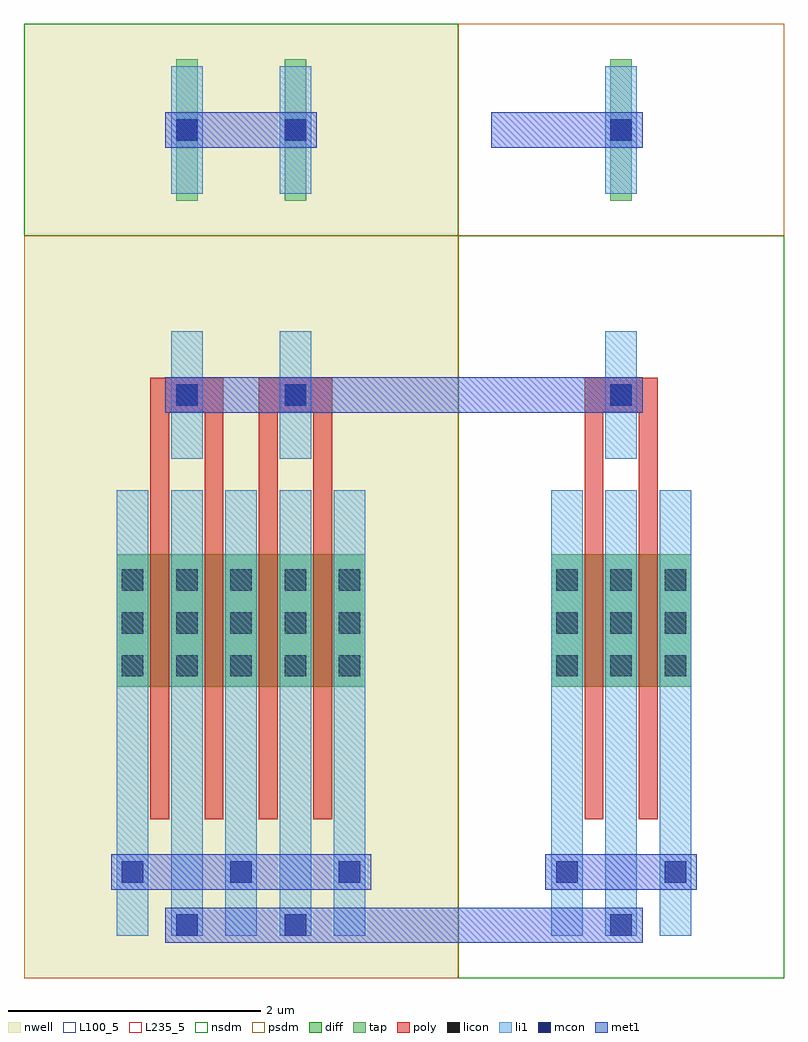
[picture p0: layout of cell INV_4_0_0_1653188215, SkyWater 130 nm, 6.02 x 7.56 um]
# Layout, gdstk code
import gdstk
lib = gdstk.Library(unit=1e-6, precision=1e-09)
def R(c, l, rs):  # rectangles x0, y0, x1, y1
    for r in rs: c.add(gdstk.rectangle(r[:2], r[2:], *l))
def A(c, l, x, y, w, h, nx, ny, dx, dy):  # array of equal rectangles
    R(c, l, [(x+i*dx, y+j*dy, x+i*dx+w, y+j*dy+h) for i in range(nx) for j in range(ny)])
def P(c, l, *ps):  # polygons
    for p in ps: c.add(gdstk.Polygon(p, *l))
nwell = (64, 20)
diff = (65, 20)
tap = (65, 44)
poly = (66, 20)
licon = (66, 44)
li1 = (67, 20)
mcon = (67, 44)
met1 = (68, 20)
nsdm = (93, 44)
psdm = (94, 20)
L100_5 = (100, 5)
L235_5 = (235, 5)

nmos_4t_61669136_x1_y1_1 = lib.new_cell('NMOS_4T_61669136_X1_Y1_1653188207_1653188215')
R(nmos_4t_61669136_x1_y1_1, diff, [(0.735,2.31,1.845,3.36)])
R(nmos_4t_61669136_x1_y1_1, tap, [(1.205,6.16,1.375,7.28)])
R(nmos_4t_61669136_x1_y1_1, poly, [(1,1.26,1.15,4.62), (1.43,1.26,1.58,4.62), (1,4.485,1.58,4.755)])
A(nmos_4t_61669136_x1_y1_1, licon, 0.775, 2.39, 0.17, 0.17, 3, 3, 0.43, 0.34)
R(nmos_4t_61669136_x1_y1_1, licon, [(1.205,4.535,1.375,4.705), (1.205,6.635,1.375,6.805)])
A(nmos_4t_61669136_x1_y1_1, li1, 0.735, 0.335, 0.25, 3.53, 3, 1, 0.43, 0)
R(nmos_4t_61669136_x1_y1_1, li1, [(1.165,4.115,1.415,5.125), (1.165,6.215,1.415,7.225)])
R(nmos_4t_61669136_x1_y1_1, mcon, [(1.205,0.335,1.375,0.505), (0.775,0.755,0.945,0.925), (1.635,0.755,1.805,0.925), (1.205,4.535,1.375,4.705), (1.205,6.635,1.375,6.805)])
R(nmos_4t_61669136_x1_y1_1, met1, [(0.26,0.28,1.46,0.56), (0.69,0.7,1.89,0.98), (0.26,4.48,1.46,4.76), (0.26,6.58,1.46,6.86)])
R(nmos_4t_61669136_x1_y1_1, nsdm, [(0,0,2.58,5.88)])
R(nmos_4t_61669136_x1_y1_1, psdm, [(0,5.88,2.58,7.56)])
R(nmos_4t_61669136_x1_y1_1, L100_5, [(0,0,2.58,7.56)])

pmos_4t_50440855_x2_y1_1 = lib.new_cell('PMOS_4T_50440855_X2_Y1_1653188208_1653188215')
R(pmos_4t_50440855_x2_y1_1, nwell, [(0,0,3.44,7.56)])
R(pmos_4t_50440855_x2_y1_1, diff, [(0.735,2.31,2.705,3.36)])
R(pmos_4t_50440855_x2_y1_1, tap, [(1.205,6.16,1.375,7.28), (2.065,6.16,2.235,7.28)])
A(pmos_4t_50440855_x2_y1_1, poly, 1, 1.26, 0.15, 3.36, 4, 1, 0.43, 0)
R(pmos_4t_50440855_x2_y1_1, poly, [(1,4.485,1.58,4.755), (1.86,4.485,2.44,4.755)])
A(pmos_4t_50440855_x2_y1_1, licon, 0.775, 2.39, 0.17, 0.17, 3, 3, 0.43, 0.34)
A(pmos_4t_50440855_x2_y1_1, licon, 1.635, 2.39, 0.17, 0.17, 3, 3, 0.43, 0.34)
R(pmos_4t_50440855_x2_y1_1, licon, [(1.205,4.535,1.375,4.705), (2.065,4.535,2.235,4.705), (1.205,6.635,1.375,6.805), (2.065,6.635,2.235,6.805)])
A(pmos_4t_50440855_x2_y1_1, li1, 0.735, 0.335, 0.25, 3.53, 5, 1, 0.43, 0)
R(pmos_4t_50440855_x2_y1_1, li1, [(1.165,4.115,1.415,5.125), (2.025,4.115,2.275,5.125), (1.165,6.215,1.415,7.225), (2.025,6.215,2.275,7.225)])
A(pmos_4t_50440855_x2_y1_1, mcon, 0.775, 0.755, 0.17, 0.17, 3, 1, 0.86, 0)
R(pmos_4t_50440855_x2_y1_1, mcon, [(1.205,0.335,1.375,0.505), (2.065,0.335,2.235,0.505), (1.205,4.535,1.375,4.705), (2.065,4.535,2.235,4.705), (1.205,6.635,1.375,6.805), (2.065,6.635,2.235,6.805)])
R(pmos_4t_50440855_x2_y1_1, met1, [(1.12,0.28,2.32,0.56), (0.69,0.7,2.75,0.98), (1.12,4.48,2.32,4.76), (1.12,6.58,2.32,6.86)])
R(pmos_4t_50440855_x2_y1_1, nsdm, [(0,5.88,3.44,7.56)])
R(pmos_4t_50440855_x2_y1_1, psdm, [(0,0,3.44,5.88)])
R(pmos_4t_50440855_x2_y1_1, L100_5, [(0,0,3.44,7.56)])

inv_4_0_0_1653188215 = lib.new_cell('INV_4_0_0_1653188215')
R(inv_4_0_0_1653188215, met1, [(2.15,0.28,3.87,0.56), (2.15,4.48,3.87,4.76)])
P(inv_4_0_0_1653188215, met1, [(0,0),(0,0),(0,0),(0,0)],
  [(0,0),(0,0),(0,0),(0,0)],
  [(0,0),(0,0),(0,0),(0,0)],
  [(0,0),(0,0),(0,0),(0,0)],
  [(0,0),(0,0),(0,0),(0,0)],
  [(0,0),(0,0),(0,0),(0,0)],
  [(0,0),(0,0),(0,0),(0,0)],
  [(0,0),(0,0),(0,0),(0,0)])
R(inv_4_0_0_1653188215, L235_5, [(0,0,6.02,7.56)])
inv_4_0_0_1653188215.add(gdstk.Reference(nmos_4t_61669136_x1_y1_1, (3.44,0)))
inv_4_0_0_1653188215.add(gdstk.Reference(pmos_4t_50440855_x2_y1_1, (0,0)))

lib.write_gds('INV_4_0_0_1653188215.gds')
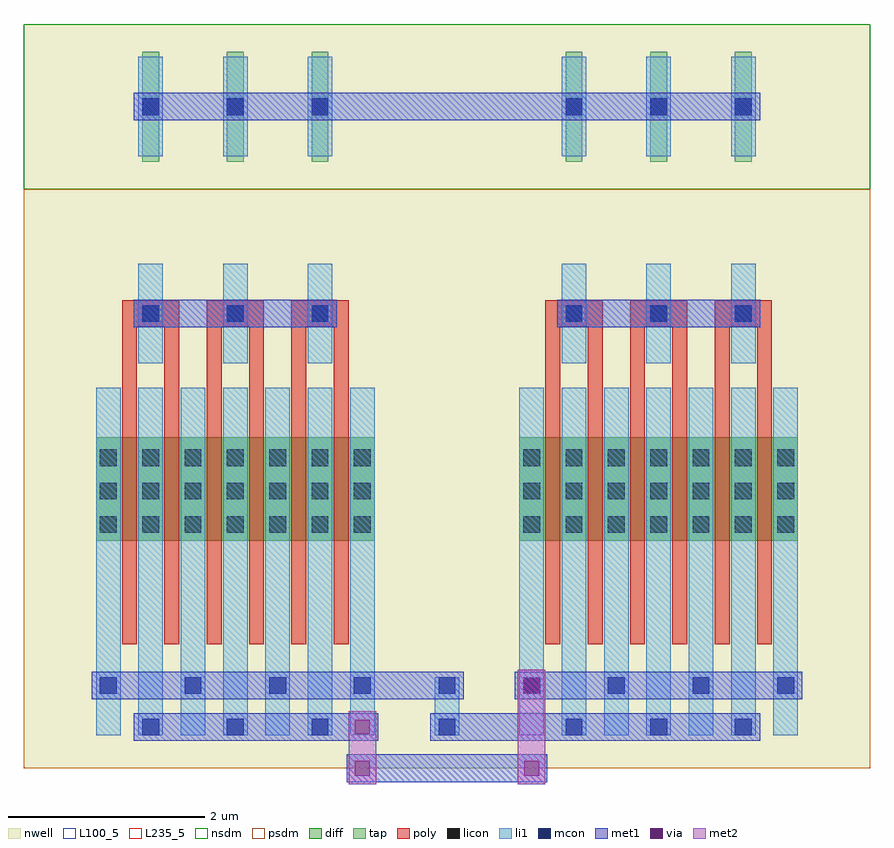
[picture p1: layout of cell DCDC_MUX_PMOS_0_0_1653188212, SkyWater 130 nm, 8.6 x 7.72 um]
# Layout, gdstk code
from math import pi, radians
import gdstk
lib = gdstk.Library(unit=1e-6, precision=1e-09)
def R(c, l, rs):  # rectangles x0, y0, x1, y1
    for r in rs: c.add(gdstk.rectangle(r[:2], r[2:], *l))
def A(c, l, x, y, w, h, nx, ny, dx, dy):  # array of equal rectangles
    R(c, l, [(x+i*dx, y+j*dy, x+i*dx+w, y+j*dy+h) for i in range(nx) for j in range(ny)])
def P(c, l, *ps):  # polygons
    for p in ps: c.add(gdstk.Polygon(p, *l))
nwell = (64, 20)
diff = (65, 20)
tap = (65, 44)
poly = (66, 20)
licon = (66, 44)
li1 = (67, 20)
mcon = (67, 44)
met1 = (68, 20)
via = (68, 44)
met2 = (69, 20)
nsdm = (93, 44)
psdm = (94, 20)
L100_5 = (100, 5)
L235_5 = (235, 5)

pmos_4t_65510288_x3_y1_1 = lib.new_cell('PMOS_4T_65510288_X3_Y1_1653188207_1653188212')
R(pmos_4t_65510288_x3_y1_1, nwell, [(0,0,4.3,7.56)])
R(pmos_4t_65510288_x3_y1_1, diff, [(0.735,2.31,3.565,3.36)])
A(pmos_4t_65510288_x3_y1_1, tap, 1.205, 6.16, 0.17, 1.12, 3, 1, 0.86, 0)
A(pmos_4t_65510288_x3_y1_1, poly, 1, 1.26, 0.15, 3.36, 6, 1, 0.43, 0)
A(pmos_4t_65510288_x3_y1_1, poly, 1, 4.485, 0.58, 0.27, 3, 1, 0.86, 0)
A(pmos_4t_65510288_x3_y1_1, licon, 0.775, 2.39, 0.17, 0.17, 3, 3, 0.43, 0.34)
A(pmos_4t_65510288_x3_y1_1, licon, 1.635, 2.39, 0.17, 0.17, 3, 3, 0.43, 0.34)
A(pmos_4t_65510288_x3_y1_1, licon, 2.495, 2.39, 0.17, 0.17, 3, 3, 0.43, 0.34)
A(pmos_4t_65510288_x3_y1_1, licon, 1.205, 4.535, 0.17, 0.17, 3, 2, 0.86, 2.1)
A(pmos_4t_65510288_x3_y1_1, li1, 0.735, 0.335, 0.25, 3.53, 7, 1, 0.43, 0)
A(pmos_4t_65510288_x3_y1_1, li1, 1.165, 4.115, 0.25, 1.01, 3, 2, 0.86, 2.1)
A(pmos_4t_65510288_x3_y1_1, mcon, 1.205, 0.335, 0.17, 0.17, 3, 2, 0.86, 4.2)
A(pmos_4t_65510288_x3_y1_1, mcon, 0.775, 0.755, 0.17, 0.17, 4, 1, 0.86, 0)
A(pmos_4t_65510288_x3_y1_1, mcon, 1.205, 6.635, 0.17, 0.17, 3, 1, 0.86, 0)
R(pmos_4t_65510288_x3_y1_1, met1, [(1.12,0.28,3.18,0.56), (0.69,0.7,3.61,0.98), (1.12,4.48,3.18,4.76), (1.12,6.58,3.18,6.86)])
R(pmos_4t_65510288_x3_y1_1, nsdm, [(0,5.88,4.3,7.56)])
R(pmos_4t_65510288_x3_y1_1, psdm, [(0,0,4.3,5.88)])
R(pmos_4t_65510288_x3_y1_1, L100_5, [(0,0,4.3,7.56)])

dcdc_mux_pmos_0_0_165318 = lib.new_cell('DCDC_MUX_PMOS_0_0_1653188212')
R(dcdc_mux_pmos_0_0_165318, li1, [(4.175,0.335,4.425,0.505), (4.175,0.335,4.425,0.505), (4.175,0.42,4.425,0.84), (4.175,0.755,4.425,0.925), (4.175,0.755,4.425,0.925)])
R(dcdc_mux_pmos_0_0_165318, mcon, [(4.215,0.335,4.385,0.505), (4.215,0.335,4.385,0.505), (4.215,0.755,4.385,0.925), (4.215,0.755,4.385,0.925)])
R(dcdc_mux_pmos_0_0_165318, met1, [(3.28,-0.14,3.6,0.14), (3.28,-0.14,3.6,0.14), (3.44,-0.14,5.16,0.14), (5,-0.14,5.32,0.14), (5,-0.14,5.32,0.14), (3.01,0.28,3.44,0.56), (3.28,0.28,3.6,0.56), (3.28,0.28,3.6,0.56), (4.13,0.28,4.47,0.56), (4.13,0.28,4.47,0.56), (4.3,0.28,5.59,0.56), (3.44,0.7,4.3,0.98), (4.13,0.7,4.47,0.98), (4.13,0.7,4.47,0.98), (5,0.7,5.32,0.98), (5,0.7,5.32,0.98), (3.01,6.58,5.59,6.86)])
P(dcdc_mux_pmos_0_0_165318, met1, [(0,0),(0,0),(0,0),(0,0)],
  [(0,0),(0,0),(0,0),(0,0)],
  [(0,0),(0,0),(0,0),(0,0)],
  [(0,0),(0,0),(0,0),(0,0)],
  [(0,0),(0,0),(0,0),(0,0)],
  [(0,0),(0,0),(0,0),(0,0)],
  [(0,0),(0,0),(0,0),(0,0)],
  [(0,0),(0,0),(0,0),(0,0)])
R(dcdc_mux_pmos_0_0_165318, via, [(3.365,-0.075,3.515,0.075), (3.365,-0.075,3.515,0.075), (5.085,-0.075,5.235,0.075), (5.085,-0.075,5.235,0.075), (3.365,0.345,3.515,0.495), (3.365,0.345,3.515,0.495), (5.085,0.765,5.235,0.915), (5.085,0.765,5.235,0.915)])
R(dcdc_mux_pmos_0_0_165318, met2, [(3.3,-0.16,3.58,0.16), (3.3,-0.16,3.58,0.16), (5.02,-0.16,5.3,0.16), (5.02,-0.16,5.3,0.16), (3.3,0,3.58,0.42), (5.02,0,5.3,0.84), (3.3,0.26,3.58,0.58), (3.3,0.26,3.58,0.58), (5.02,0.68,5.3,1), (5.02,0.68,5.3,1)])
R(dcdc_mux_pmos_0_0_165318, L235_5, [(0,0,8.6,7.56)])
dcdc_mux_pmos_0_0_165318.add(gdstk.Reference(pmos_4t_65510288_x3_y1_1, (8.6,0), rotation=pi, x_reflection=True))
dcdc_mux_pmos_0_0_165318.add(gdstk.Reference(pmos_4t_65510288_x3_y1_1, (0,0)))

lib.write_gds('DCDC_MUX_PMOS_0_0_1653188212.gds')
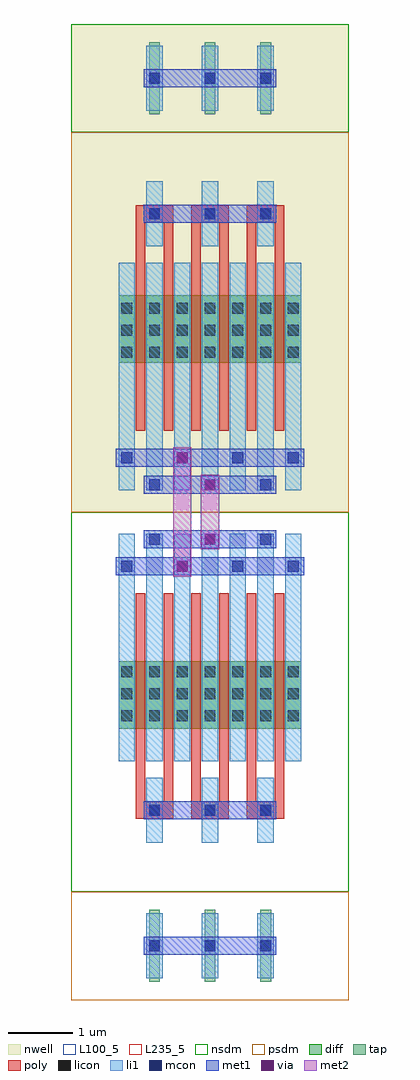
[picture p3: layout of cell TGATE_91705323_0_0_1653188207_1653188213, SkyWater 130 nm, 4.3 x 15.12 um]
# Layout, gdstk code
import gdstk
lib = gdstk.Library(unit=1e-6, precision=1e-09)
def R(c, l, rs):  # rectangles x0, y0, x1, y1
    for r in rs: c.add(gdstk.rectangle(r[:2], r[2:], *l))
def A(c, l, x, y, w, h, nx, ny, dx, dy):  # array of equal rectangles
    R(c, l, [(x+i*dx, y+j*dy, x+i*dx+w, y+j*dy+h) for i in range(nx) for j in range(ny)])
def P(c, l, *ps):  # polygons
    for p in ps: c.add(gdstk.Polygon(p, *l))
nwell = (64, 20)
diff = (65, 20)
tap = (65, 44)
poly = (66, 20)
licon = (66, 44)
li1 = (67, 20)
mcon = (67, 44)
met1 = (68, 20)
via = (68, 44)
met2 = (69, 20)
nsdm = (93, 44)
psdm = (94, 20)
L100_5 = (100, 5)
L235_5 = (235, 5)

nmos_4t_65109672_x3_y1_1 = lib.new_cell('NMOS_4T_65109672_X3_Y1_1653188207_1653188207_1653188213')
R(nmos_4t_65109672_x3_y1_1, diff, [(0.735,2.31,3.565,3.36)])
A(nmos_4t_65109672_x3_y1_1, tap, 1.205, 6.16, 0.17, 1.12, 3, 1, 0.86, 0)
A(nmos_4t_65109672_x3_y1_1, poly, 1, 1.26, 0.15, 3.36, 6, 1, 0.43, 0)
A(nmos_4t_65109672_x3_y1_1, poly, 1, 4.485, 0.58, 0.27, 3, 1, 0.86, 0)
A(nmos_4t_65109672_x3_y1_1, licon, 0.775, 2.39, 0.17, 0.17, 3, 3, 0.43, 0.34)
A(nmos_4t_65109672_x3_y1_1, licon, 1.635, 2.39, 0.17, 0.17, 3, 3, 0.43, 0.34)
A(nmos_4t_65109672_x3_y1_1, licon, 2.495, 2.39, 0.17, 0.17, 3, 3, 0.43, 0.34)
A(nmos_4t_65109672_x3_y1_1, licon, 1.205, 4.535, 0.17, 0.17, 3, 2, 0.86, 2.1)
A(nmos_4t_65109672_x3_y1_1, li1, 0.735, 0.335, 0.25, 3.53, 7, 1, 0.43, 0)
A(nmos_4t_65109672_x3_y1_1, li1, 1.165, 4.115, 0.25, 1.01, 3, 2, 0.86, 2.1)
A(nmos_4t_65109672_x3_y1_1, mcon, 1.205, 0.335, 0.17, 0.17, 3, 2, 0.86, 4.2)
A(nmos_4t_65109672_x3_y1_1, mcon, 0.775, 0.755, 0.17, 0.17, 4, 1, 0.86, 0)
A(nmos_4t_65109672_x3_y1_1, mcon, 1.205, 6.635, 0.17, 0.17, 3, 1, 0.86, 0)
R(nmos_4t_65109672_x3_y1_1, met1, [(1.12,0.28,3.18,0.56), (0.69,0.7,3.61,0.98), (1.12,4.48,3.18,4.76), (1.12,6.58,3.18,6.86)])
R(nmos_4t_65109672_x3_y1_1, nsdm, [(0,0,4.3,5.88)])
R(nmos_4t_65109672_x3_y1_1, psdm, [(0,5.88,4.3,7.56)])
R(nmos_4t_65109672_x3_y1_1, L100_5, [(0,0,4.3,7.56)])

pmos_4t_65510288_x3_y1_1 = lib.new_cell('PMOS_4T_65510288_X3_Y1_1653188208_1653188207_1653188213')
R(pmos_4t_65510288_x3_y1_1, nwell, [(0,0,4.3,7.56)])
R(pmos_4t_65510288_x3_y1_1, diff, [(0.735,2.31,3.565,3.36)])
A(pmos_4t_65510288_x3_y1_1, tap, 1.205, 6.16, 0.17, 1.12, 3, 1, 0.86, 0)
A(pmos_4t_65510288_x3_y1_1, poly, 1, 1.26, 0.15, 3.36, 6, 1, 0.43, 0)
A(pmos_4t_65510288_x3_y1_1, poly, 1, 4.485, 0.58, 0.27, 3, 1, 0.86, 0)
A(pmos_4t_65510288_x3_y1_1, licon, 0.775, 2.39, 0.17, 0.17, 3, 3, 0.43, 0.34)
A(pmos_4t_65510288_x3_y1_1, licon, 1.635, 2.39, 0.17, 0.17, 3, 3, 0.43, 0.34)
A(pmos_4t_65510288_x3_y1_1, licon, 2.495, 2.39, 0.17, 0.17, 3, 3, 0.43, 0.34)
A(pmos_4t_65510288_x3_y1_1, licon, 1.205, 4.535, 0.17, 0.17, 3, 2, 0.86, 2.1)
A(pmos_4t_65510288_x3_y1_1, li1, 0.735, 0.335, 0.25, 3.53, 7, 1, 0.43, 0)
A(pmos_4t_65510288_x3_y1_1, li1, 1.165, 4.115, 0.25, 1.01, 3, 2, 0.86, 2.1)
A(pmos_4t_65510288_x3_y1_1, mcon, 1.205, 0.335, 0.17, 0.17, 3, 2, 0.86, 4.2)
A(pmos_4t_65510288_x3_y1_1, mcon, 0.775, 0.755, 0.17, 0.17, 4, 1, 0.86, 0)
A(pmos_4t_65510288_x3_y1_1, mcon, 1.205, 6.635, 0.17, 0.17, 3, 1, 0.86, 0)
R(pmos_4t_65510288_x3_y1_1, met1, [(1.12,0.28,3.18,0.56), (0.69,0.7,3.61,0.98), (1.12,4.48,3.18,4.76), (1.12,6.58,3.18,6.86)])
R(pmos_4t_65510288_x3_y1_1, nsdm, [(0,5.88,4.3,7.56)])
R(pmos_4t_65510288_x3_y1_1, psdm, [(0,0,4.3,5.88)])
R(pmos_4t_65510288_x3_y1_1, L100_5, [(0,0,4.3,7.56)])

tgate_91705323_0_0_16531 = lib.new_cell('TGATE_91705323_0_0_1653188207_1653188213')
R(tgate_91705323_0_0_16531, met1, [(1.56,6.58,1.88,6.86), (1.56,6.58,1.88,6.86), (1.99,7,2.31,7.28), (1.99,7,2.31,7.28), (1.99,7.84,2.31,8.12), (1.99,7.84,2.31,8.12), (1.56,8.26,1.88,8.54), (1.56,8.26,1.88,8.54)])
P(tgate_91705323_0_0_16531, met1, [(0,0),(0,0),(0,0),(0,0)],
  [(0,0),(0,0),(0,0),(0,0)],
  [(0,0),(0,0),(0,0),(0,0)],
  [(0,0),(0,0),(0,0),(0,0)],
  [(0,0),(0,0),(0,0),(0,0)],
  [(0,0),(0,0),(0,0),(0,0)],
  [(0,0),(0,0),(0,0),(0,0)],
  [(0,0),(0,0),(0,0),(0,0)])
R(tgate_91705323_0_0_16531, via, [(1.645,6.645,1.795,6.795), (1.645,6.645,1.795,6.795), (2.075,7.065,2.225,7.215), (2.075,7.065,2.225,7.215), (2.075,7.905,2.225,8.055), (2.075,7.905,2.225,8.055), (1.645,8.325,1.795,8.475), (1.645,8.325,1.795,8.475)])
R(tgate_91705323_0_0_16531, met2, [(1.58,6.56,1.86,6.88), (1.58,6.56,1.86,6.88), (1.58,6.72,1.86,8.4), (2.01,6.98,2.29,7.3), (2.01,6.98,2.29,7.3), (2.01,7.14,2.29,7.98), (2.01,7.82,2.29,8.14), (2.01,7.82,2.29,8.14), (1.58,8.24,1.86,8.56), (1.58,8.24,1.86,8.56)])
R(tgate_91705323_0_0_16531, L235_5, [(0,0,4.3,15.12)])
tgate_91705323_0_0_16531.add(gdstk.Reference(nmos_4t_65109672_x3_y1_1, (0,7.56), x_reflection=True))
tgate_91705323_0_0_16531.add(gdstk.Reference(pmos_4t_65510288_x3_y1_1, (0,7.56)))

lib.write_gds('TGATE_91705323_0_0_1653188207_1653188213.gds')
